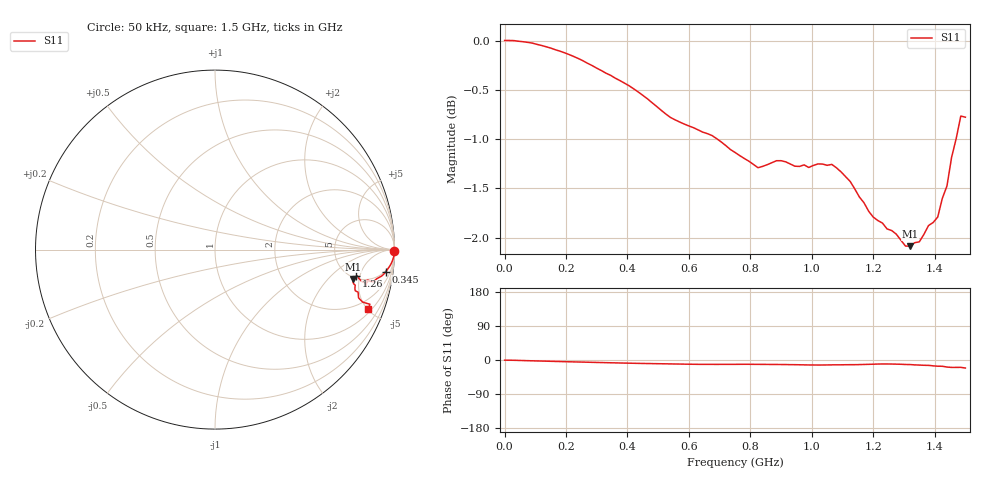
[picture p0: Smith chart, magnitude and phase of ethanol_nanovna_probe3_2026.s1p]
! Touchstone S1P file exported from NanoVNA UTN Toolkit
! Device: NanoVNA-H
! Export date: 2026-10-13 11:31:14
! Frequency range: 0.050 - 1500.000 MHz
! Number of points: 101
! Parameter: S11 (Reflection)
# Hz S RI R 50
! f[Hz]  S11_real S11_imag
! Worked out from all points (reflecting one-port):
!   101 points, 50 kHz to 1.5 GHz, reference 50 ohm
!   lowest |S11| = -2.1 dB at 1.32 GHz (marker M1), VSWR 8.37, Z = 238 - j205 ohm
!   phase of S11 starts at -0 deg and turns -21 deg over the sweep
!   S11 on the Smith chart (normalised r, x): 50 kHz: open; 345 MHz: 5, -14; 1.26 GHz: 5.32, -4.41; 1.5 GHz: 1.25, -5.05
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50000  1 -0.00795
3.0049e7  0.9998 -0.0128
1.950435e8  0.9829 -0.0758
3.450385e8  0.9524 -0.1223
3.750375e8  0.9454 -0.1306
4.350355e8  0.9303 -0.1458
5.70031e8  0.8934 -0.1688
6.450285e8  0.8805 -0.179
7.50025e8  0.8601 -0.1738
8.250225e8  0.8446 -0.1724
8.850205e8  0.8507 -0.1777
9.450185e8  0.8435 -0.1849
1.020016e9  0.8427 -0.1986
1.065014e9  0.8437 -0.1921
1.140012e9  0.8214 -0.1799
1.20001e9  0.7985 -0.1562
1.230009e9  0.7946 -0.1463
1.260008e9  0.7872 -0.1484
1.305006e9  0.7699 -0.1613
1.320006e9  0.7692 -0.1642
1.350005e9  0.7691 -0.183
1.380004e9  0.7811 -0.1975
1.410003e9  0.7809 -0.229
1.425002e9  0.7973 -0.2371
1.440002e9  0.7998 -0.2688
1.455002e9  0.822 -0.2921
1.485e9  0.8634 -0.3046
1.5e9  0.8526 -0.3304
